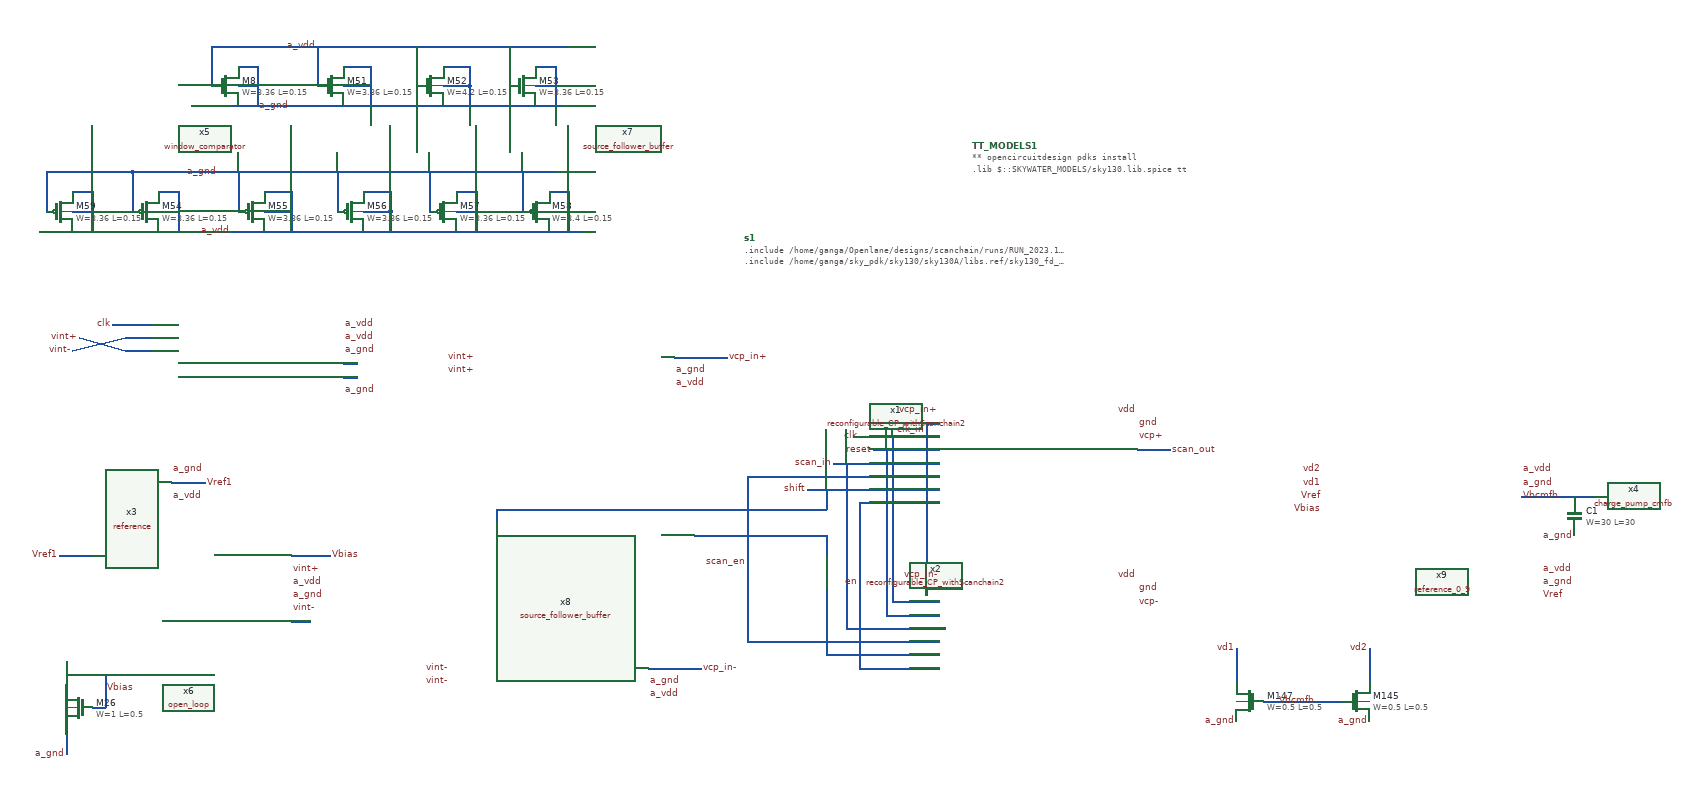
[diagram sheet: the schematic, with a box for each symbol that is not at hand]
v {xschem version=3.4.4 file_version=1.2
}
G {}
K {}
V {}
S {}
E {}
N -90 210 -40 210 {
lab=clk}
N -40 210 40 210 {
lab=clk}
N -30 210 -30 460 {
lab=clk}
N -30 460 30 460 {
lab=clk}
N 30 460 40 460 {
lab=clk}
N 20 190 40 190 {
lab=clk_in}
N 20 190 20 450 {
lab=clk_in}
N 20 440 40 440 {
lab=clk_in}
N -60 230 40 230 {
lab=reset}
N -40 230 -40 480 {
lab=reset}
N -40 480 40 480 {
lab=reset}
N -120 250 40 250 {
lab=scan_in}
N -160 290 40 290 {
lab=shift}
N -130 290 -130 310 {
lab=shift}
N -130 390 -130 540 {
lab=#net1}
N -130 540 40 540 {
lab=#net1}
N -80 310 40 310 {
lab=en}
N -80 310 -80 560 {
lab=en}
N -80 560 30 560 {
lab=en}
N 30 560 40 560 {
lab=en}
N -250 270 40 270 {
lab=scan_en}
N -250 270 -250 520 {
lab=scan_en}
N -250 520 40 520 {
lab=scan_en}
N -100 250 -100 490 {
lab=scan_in}
N -100 490 -100 500 {
lab=scan_in}
N -100 500 50 500 {
lab=scan_in}
N 340 230 390 230 {
lab=scan_out}
N -330 360 -130 360 {
lab=#net1}
N -130 360 -130 400 {
lab=#net1}
N -130 310 -130 320 {
lab=shift}
N -630 320 -130 320 {
lab=shift}
N -630 320 -630 340 {
lab=shift}
N 530 610 650 610 {
lab=Vbcmfb}
N 490 530 490 580 {
lab=vd1}
N 690 530 690 580 {
lab=vd2}
N -860 100 -840 100 {
lab=#net2}
N -860 120 -840 120 {
lab=#net3}
N -1210 40 -1150 40 {
lab=clk}
N -1190 60 -1150 60 {
lab=vint-}
N -1190 80 -1150 80 {
lab=vint+}
N -940 490 -910 490 {
lab=#net4}
N -940 390 -880 390 {
lab=Vbias}
N -1290 390 -1240 390 {
lab=Vref1}
N -1280 550 -1280 590 {
lab=Vbias}
N -1240 620 -1220 620 {
lab=Vbias}
N -1220 570 -1220 620 {
lab=Vbias}
N -1280 570 -1220 570 {
lab=Vbias}
N -1280 650 -1280 690 {
lab=a_gnd}
N -1280 620 -1280 660 {
lab=a_gnd}
N 920 300 1030 300 {
lab=Vbcmfb}
N -1020 -350 -990 -350 {
lab=a_gnd}
N -990 -350 -990 -290 {
lab=a_gnd}
N -1020 -290 -990 -290 {
lab=a_gnd}
N -1020 -320 -990 -320 {
lab=a_gnd}
N -1090 -290 -640 -290 {
lab=a_gnd}
N -1060 -350 -1060 -320 {
lab=a_vdd}
N -900 -350 -900 -320 {
lab=a_vdd}
N -1060 -380 -1060 -350 {
lab=a_vdd}
N -1060 -380 -640 -380 {
lab=a_vdd}
N -900 -380 -900 -350 {
lab=a_vdd}
N -860 -350 -820 -350 {
lab=a_gnd}
N -820 -350 -820 -290 {
lab=a_gnd}
N -860 -320 -820 -320 {
lab=a_gnd}
N -750 -380 -750 -320 {
lab=a_vdd}
N -710 -320 -670 -320 {
lab=a_gnd}
N -670 -320 -670 -290 {
lab=a_gnd}
N -710 -350 -670 -350 {
lab=a_gnd}
N -670 -350 -670 -320 {
lab=a_gnd}
N -640 -380 -520 -380 {
lab=a_vdd}
N -640 -290 -530 -290 {
lab=a_gnd}
N -610 -380 -610 -320 {
lab=a_vdd}
N -570 -350 -540 -350 {
lab=a_gnd}
N -540 -350 -540 -290 {
lab=a_gnd}
N -570 -320 -540 -320 {
lab=a_gnd}
N -1140 -160 -1110 -160 {
lab=a_vdd}
N -1110 -160 -1110 -100 {
lab=a_vdd}
N -1140 -100 -1110 -100 {
lab=a_vdd}
N -1140 -130 -1110 -130 {
lab=a_vdd}
N -1210 -100 -760 -100 {
lab=a_vdd}
N -1180 -160 -1180 -130 {
lab=a_gnd}
N -1020 -160 -1020 -130 {
lab=a_gnd}
N -1180 -190 -1180 -160 {
lab=a_gnd}
N -1180 -190 -760 -190 {
lab=a_gnd}
N -1020 -190 -1020 -160 {
lab=a_gnd}
N -980 -160 -940 -160 {
lab=a_vdd}
N -940 -160 -940 -100 {
lab=a_vdd}
N -980 -130 -940 -130 {
lab=a_vdd}
N -870 -190 -870 -130 {
lab=a_gnd}
N -830 -130 -790 -130 {
lab=a_vdd}
N -790 -130 -790 -100 {
lab=a_vdd}
N -830 -160 -790 -160 {
lab=a_vdd}
N -790 -160 -790 -130 {
lab=a_vdd}
N -760 -190 -640 -190 {
lab=a_gnd}
N -760 -100 -650 -100 {
lab=a_vdd}
N -730 -190 -730 -130 {
lab=a_gnd}
N -690 -160 -660 -160 {
lab=a_vdd}
N -660 -160 -660 -100 {
lab=a_vdd}
N -690 -130 -660 -130 {
lab=a_vdd}
N -640 -190 -540 -190 {
lab=a_gnd}
N -650 -100 -500 -100 {
lab=a_vdd}
N -550 -160 -520 -160 {
lab=a_vdd}
N -520 -160 -520 -100 {
lab=a_vdd}
N -550 -130 -520 -130 {
lab=a_vdd}
N -590 -190 -590 -130 {
lab=a_gnd}
N -1310 -190 -1180 -190 {
lab=a_gnd}
N -1320 -100 -1210 -100 {
lab=a_vdd}
N -1310 -190 -1310 -130 {
lab=a_gnd}
N -1270 -160 -1240 -160 {
lab=a_vdd}
N -1240 -160 -1240 -100 {
lab=a_vdd}
N -1270 -130 -1240 -130 {
lab=a_vdd}
N -360 90 -280 90 {
lab=vcp_in+}
N -400 560 -320 560 {
lab=vcp_in-}
N -1260 60 -1190 80 {
lab=vint+}
N -1270 80 -1190 60 {
lab=vint-}
N -1120 280 -1070 280 {
lab=Vref1}
C {devices/code_shown.sym} -255 -90 0 0 {name=s1 only_toplevel=false value="
.include /home/ganga/Openlane/designs/scanchain/runs/RUN_2023.10.30_16.04.26/results/signoff/scanchain.spice
.include /home/ganga/sky_pdk/sky130/sky130A/libs.ref/sky130_fd_sc_hd/spice/sky130_fd_sc_hd.spice
"}
C {reconfigurable_CP_withScanchain2.sym} 190 240 0 0 {name=x1}
C {reconfigurable_CP_withScanchain2.sym} 190 490 0 0 {name=x2}
C {devices/lab_pin.sym} 340 170 1 0 {name=p143 sig_type=std_logic lab=vdd}
C {devices/lab_pin.sym} 340 190 2 0 {name=p190 sig_type=std_logic lab=gnd}
C {devices/lab_pin.sym} 340 210 2 0 {name=p1 sig_type=std_logic lab=vcp+}
C {devices/lab_pin.sym} 340 420 1 0 {name=p2 sig_type=std_logic lab=vdd}
C {devices/lab_pin.sym} 340 440 2 0 {name=p3 sig_type=std_logic lab=gnd}
C {devices/lab_pin.sym} 340 460 2 0 {name=p4 sig_type=std_logic lab=vcp-}
C {devices/lab_pin.sym} -60 230 2 1 {name=p139 sig_type=std_logic lab=reset
}
C {devices/lab_pin.sym} -250 400 2 1 {name=p140 sig_type=std_logic lab=scan_en
}
C {devices/lab_pin.sym} -80 210 2 1 {name=p142 sig_type=std_logic lab=clk
}
C {devices/lab_pin.sym} -80 430 2 1 {name=p6 sig_type=std_logic lab=en
}
C {devices/lab_pin.sym} -160 290 2 1 {name=p7 sig_type=std_logic lab=shift
}
C {devices/lab_pin.sym} 20 200 2 1 {name=p5 sig_type=std_logic lab=clk_in
}
C {devices/lab_pin.sym} 40 170 2 1 {name=p8 sig_type=std_logic lab=vcp_in+
}
C {devices/lab_pin.sym} 40 420 2 1 {name=p9 sig_type=std_logic lab=vcp_in-
}
C {devices/lab_pin.sym} -120 250 2 1 {name=p10 sig_type=std_logic lab=scan_in
}
C {devices/lab_pin.sym} 390 230 0 1 {name=p11 sig_type=std_logic lab=scan_out
}
C {devices/code.sym} 90 -230 0 0 {name=TT_MODELS1
only_toplevel=true
format="tcleval( @value )"
value="
** opencircuitdesign pdks install
.lib $::SKYWATER_MODELS/sky130.lib.spice tt

"
spice_ignore=false}
C {sky130_fd_pr/nfet_01v8.sym} 670 610 0 0 {name=M145
L=0.5
W=0.5
nf=1 
mult=1
ad="'int((nf+1)/2) * W/nf * 0.29'" 
pd="'2*int((nf+1)/2) * (W/nf + 0.29)'"
as="'int((nf+2)/2) * W/nf * 0.29'" 
ps="'2*int((nf+2)/2) * (W/nf + 0.29)'"
nrd="'0.29 / W'" nrs="'0.29 / W'"
sa=0 sb=0 sd=0
model=nfet_01v8
spiceprefix=X
}
C {sky130_fd_pr/nfet_01v8.sym} 510 610 0 1 {name=M147
L=0.5
W=0.5
nf=1 
mult=1
ad="'int((nf+1)/2) * W/nf * 0.29'" 
pd="'2*int((nf+1)/2) * (W/nf + 0.29)'"
as="'int((nf+2)/2) * W/nf * 0.29'" 
ps="'2*int((nf+2)/2) * (W/nf + 0.29)'"
nrd="'0.29 / W'" nrs="'0.29 / W'"
sa=0 sb=0 sd=0
model=nfet_01v8
spiceprefix=X
}
C {devices/lab_wire.sym} 610 610 0 0 {name=p629 sig_type=std_logic lab=Vbcmfb




}
C {devices/lab_wire.sym} 490 530 0 0 {name=p22 sig_type=std_logic lab=vd1

}
C {devices/lab_wire.sym} 690 530 0 0 {name=p23 sig_type=std_logic lab=vd2


}
C {devices/lab_wire.sym} 490 640 3 0 {name=p34 sig_type=std_logic lab=a_gnd





}
C {devices/lab_wire.sym} 690 640 3 0 {name=p35 sig_type=std_logic lab=a_gnd





}
C {charge_pump_cmfb.sym} 770 290 0 0 {name=x4}
C {devices/lab_wire.sym} 620 300 0 0 {name=p24 sig_type=std_logic lab=Vref
}
C {devices/lab_wire.sym} 620 280 0 0 {name=p25 sig_type=std_logic lab=vd1

}
C {devices/lab_wire.sym} 620 260 0 0 {name=p26 sig_type=std_logic lab=vd2


}
C {devices/lab_wire.sym} 620 320 0 0 {name=p27 sig_type=std_logic lab=Vbias
}
C {devices/lab_wire.sym} 920 300 2 0 {name=p28 sig_type=std_logic lab=Vbcmfb




}
C {devices/lab_pin.sym} 920 260 2 0 {name=p29 sig_type=std_logic lab=a_vdd}
C {devices/lab_pin.sym} 920 280 2 0 {name=p30 sig_type=std_logic lab=a_gnd}
C {window_comparator.sym} -1010 90 0 0 {name=x5}
C {open_loop.sym} -1090 440 0 0 {name=x6}
C {devices/lab_wire.sym} -940 450 0 1 {name=p31 sig_type=std_logic lab=a_gnd
}
C {devices/lab_wire.sym} -860 80 0 1 {name=p32 sig_type=std_logic lab=a_gnd
}
C {devices/lab_wire.sym} -940 430 0 1 {name=p33 sig_type=std_logic lab=a_vdd
}
C {devices/lab_wire.sym} -860 60 0 1 {name=p36 sig_type=std_logic lab=a_vdd
}
C {devices/lab_wire.sym} -1210 40 0 0 {name=p37 sig_type=std_logic lab=clk



}
C {devices/lab_wire.sym} -1260 60 0 0 {name=p38 sig_type=std_logic lab=vint+



}
C {devices/lab_wire.sym} -1270 80 0 0 {name=p39 sig_type=std_logic lab=vint-



}
C {devices/lab_wire.sym} -940 410 0 1 {name=p40 sig_type=std_logic lab=vint+



}
C {devices/lab_wire.sym} -940 470 0 1 {name=p41 sig_type=std_logic lab=vint-



}
C {devices/lab_wire.sym} -1220 590 0 1 {name=p42 sig_type=std_logic lab=Vbias

}
C {sky130_fd_pr/nfet_01v8.sym} -1260 620 0 1 {name=M26
L=0.5
W=1
nf=1 
mult=1
ad="'int((nf+1)/2) * W/nf * 0.29'" 
pd="'2*int((nf+1)/2) * (W/nf + 0.29)'"
as="'int((nf+2)/2) * W/nf * 0.29'" 
ps="'2*int((nf+2)/2) * (W/nf + 0.29)'"
nrd="'0.29 / W'" nrs="'0.29 / W'"
sa=0 sb=0 sd=0
model=nfet_01v8
spiceprefix=X
}
C {devices/lab_wire.sym} -880 390 0 1 {name=p44 sig_type=std_logic lab=Vbias

}
C {devices/lab_wire.sym} -1290 390 0 0 {name=p45 sig_type=std_logic lab=Vref1
}
C {devices/lab_wire.sym} -1280 690 0 0 {name=p43 sig_type=std_logic lab=a_gnd
}
C {sky130_fd_pr/cap_mim_m3_1.sym} 1000 330 0 0 {name=C1 model=cap_mim_m3_1 W=30 L=30 MF=1 spiceprefix=X}
C {devices/lab_wire.sym} 1000 360 3 0 {name=p51 sig_type=std_logic lab=a_gnd





}
C {sky130_fd_pr/nfet_01v8.sym} -1040 -320 0 0 {name=M8
L=0.15
W=3.36
nf=8 
mult=1
ad="'int((nf+1)/2) * W/nf * 0.29'" 
pd="'2*int((nf+1)/2) * (W/nf + 0.29)'"
as="'int((nf+2)/2) * W/nf * 0.29'" 
ps="'2*int((nf+2)/2) * (W/nf + 0.29)'"
nrd="'0.29 / W'" nrs="'0.29 / W'"
sa=0 sb=0 sd=0
model=nfet_01v8
spiceprefix=X
}
C {devices/lab_wire.sym} -990 -290 0 1 {name=p52 sig_type=std_logic lab=a_gnd

}
C {devices/lab_wire.sym} -900 -380 0 0 {name=p53 sig_type=std_logic lab=a_vdd




}
C {sky130_fd_pr/nfet_01v8.sym} -880 -320 0 0 {name=M51
L=0.15
W=3.36
nf=8 
mult=1
ad="'int((nf+1)/2) * W/nf * 0.29'" 
pd="'2*int((nf+1)/2) * (W/nf + 0.29)'"
as="'int((nf+2)/2) * W/nf * 0.29'" 
ps="'2*int((nf+2)/2) * (W/nf + 0.29)'"
nrd="'0.29 / W'" nrs="'0.29 / W'"
sa=0 sb=0 sd=0
model=nfet_01v8
spiceprefix=X
}
C {sky130_fd_pr/nfet_01v8.sym} -730 -320 0 0 {name=M52
L=0.15
W=4.2
nf=10
mult=1
ad="'int((nf+1)/2) * W/nf * 0.29'" 
pd="'2*int((nf+1)/2) * (W/nf + 0.29)'"
as="'int((nf+2)/2) * W/nf * 0.29'" 
ps="'2*int((nf+2)/2) * (W/nf + 0.29)'"
nrd="'0.29 / W'" nrs="'0.29 / W'"
sa=0 sb=0 sd=0
model=nfet_01v8
spiceprefix=X
}
C {sky130_fd_pr/nfet_01v8.sym} -590 -320 0 0 {name=M53
L=0.15
W=3.36
nf=8
mult=1
ad="'int((nf+1)/2) * W/nf * 0.29'" 
pd="'2*int((nf+1)/2) * (W/nf + 0.29)'"
as="'int((nf+2)/2) * W/nf * 0.29'" 
ps="'2*int((nf+2)/2) * (W/nf + 0.29)'"
nrd="'0.29 / W'" nrs="'0.29 / W'"
sa=0 sb=0 sd=0
model=nfet_01v8
spiceprefix=X
}
C {devices/lab_wire.sym} -1100 -190 0 1 {name=p69 sig_type=std_logic lab=a_gnd

}
C {devices/lab_wire.sym} -1030 -100 0 0 {name=p70 sig_type=std_logic lab=a_vdd




}
C {sky130_fd_pr/pfet_01v8.sym} -1160 -130 0 0 {name=M54
L=0.15
W=3.36
nf=8
mult=1
ad="'int((nf+1)/2) * W/nf * 0.29'" 
pd="'2*int((nf+1)/2) * (W/nf + 0.29)'"
as="'int((nf+2)/2) * W/nf * 0.29'" 
ps="'2*int((nf+2)/2) * (W/nf + 0.29)'"
nrd="'0.29 / W'" nrs="'0.29 / W'"
sa=0 sb=0 sd=0
model=pfet_01v8
spiceprefix=X
}
C {sky130_fd_pr/pfet_01v8.sym} -1000 -130 0 0 {name=M55
L=0.15
W=3.36
nf=8
mult=1
ad="'int((nf+1)/2) * W/nf * 0.29'" 
pd="'2*int((nf+1)/2) * (W/nf + 0.29)'"
as="'int((nf+2)/2) * W/nf * 0.29'" 
ps="'2*int((nf+2)/2) * (W/nf + 0.29)'"
nrd="'0.29 / W'" nrs="'0.29 / W'"
sa=0 sb=0 sd=0
model=pfet_01v8
spiceprefix=X
}
C {sky130_fd_pr/pfet_01v8.sym} -850 -130 0 0 {name=M56
L=0.15
W=3.36
nf=8
mult=1
ad="'int((nf+1)/2) * W/nf * 0.29'" 
pd="'2*int((nf+1)/2) * (W/nf + 0.29)'"
as="'int((nf+2)/2) * W/nf * 0.29'" 
ps="'2*int((nf+2)/2) * (W/nf + 0.29)'"
nrd="'0.29 / W'" nrs="'0.29 / W'"
sa=0 sb=0 sd=0
model=pfet_01v8
spiceprefix=X
}
C {sky130_fd_pr/pfet_01v8.sym} -710 -130 0 0 {name=M57
L=0.15
W=3.36
nf=8
mult=1
ad="'int((nf+1)/2) * W/nf * 0.29'" 
pd="'2*int((nf+1)/2) * (W/nf + 0.29)'"
as="'int((nf+2)/2) * W/nf * 0.29'" 
ps="'2*int((nf+2)/2) * (W/nf + 0.29)'"
nrd="'0.29 / W'" nrs="'0.29 / W'"
sa=0 sb=0 sd=0
model=pfet_01v8
spiceprefix=X
}
C {sky130_fd_pr/pfet_01v8.sym} -570 -130 0 0 {name=M58
L=0.15
W=8.4
nf=20
mult=1
ad="'int((nf+1)/2) * W/nf * 0.29'" 
pd="'2*int((nf+1)/2) * (W/nf + 0.29)'"
as="'int((nf+2)/2) * W/nf * 0.29'" 
ps="'2*int((nf+2)/2) * (W/nf + 0.29)'"
nrd="'0.29 / W'" nrs="'0.29 / W'"
sa=0 sb=0 sd=0
model=pfet_01v8
spiceprefix=X
}
C {sky130_fd_pr/pfet_01v8.sym} -1290 -130 0 0 {name=M59
L=0.15
W=3.36
nf=8
mult=1
ad="'int((nf+1)/2) * W/nf * 0.29'" 
pd="'2*int((nf+1)/2) * (W/nf + 0.29)'"
as="'int((nf+2)/2) * W/nf * 0.29'" 
ps="'2*int((nf+2)/2) * (W/nf + 0.29)'"
nrd="'0.29 / W'" nrs="'0.29 / W'"
sa=0 sb=0 sd=0
model=pfet_01v8
spiceprefix=X
}
C {source_follower_buffer.sym} -510 110 0 0 {name=x7}
C {devices/lab_wire.sym} -660 90 0 0 {name=p14 sig_type=std_logic lab=vint+



}
C {devices/lab_wire.sym} -660 110 0 0 {name=p15 sig_type=std_logic lab=vint+



}
C {devices/lab_wire.sym} -360 130 0 1 {name=p16 sig_type=std_logic lab=a_vdd
}
C {devices/lab_wire.sym} -360 110 0 1 {name=p17 sig_type=std_logic lab=a_gnd
}
C {devices/lab_pin.sym} -280 90 2 0 {name=p18 sig_type=std_logic lab=vcp_in+
}
C {source_follower_buffer.sym} -550 580 0 0 {name=x8}
C {devices/lab_wire.sym} -700 560 0 0 {name=p19 sig_type=std_logic lab=vint-



}
C {devices/lab_wire.sym} -700 580 0 0 {name=p20 sig_type=std_logic lab=vint-



}
C {devices/lab_wire.sym} -400 600 0 1 {name=p21 sig_type=std_logic lab=a_vdd
}
C {devices/lab_wire.sym} -400 580 0 1 {name=p54 sig_type=std_logic lab=a_gnd
}
C {devices/lab_pin.sym} -320 560 2 0 {name=p55 sig_type=std_logic lab=vcp_in-
}
C {devices/lab_wire.sym} -860 40 0 1 {name=p47 sig_type=std_logic lab=a_vdd
}
C {devices/lab_wire.sym} -860 140 0 1 {name=p48 sig_type=std_logic lab=a_gnd
}
C {reference.sym} -1270 290 0 0 {name=x3}
C {devices/lab_wire.sym} -1120 300 0 1 {name=p49 sig_type=std_logic lab=a_vdd
}
C {devices/lab_wire.sym} -1120 260 0 1 {name=p50 sig_type=std_logic lab=a_gnd
}
C {devices/lab_wire.sym} -1070 280 0 1 {name=p56 sig_type=std_logic lab=Vref1
}
C {reference_0_9.sym} 800 430 0 0 {name=x9}
C {devices/lab_pin.sym} 950 410 2 0 {name=p46 sig_type=std_logic lab=a_vdd}
C {devices/lab_pin.sym} 950 430 2 0 {name=p57 sig_type=std_logic lab=a_gnd}
C {devices/lab_wire.sym} 950 450 0 1 {name=p58 sig_type=std_logic lab=Vref
}
